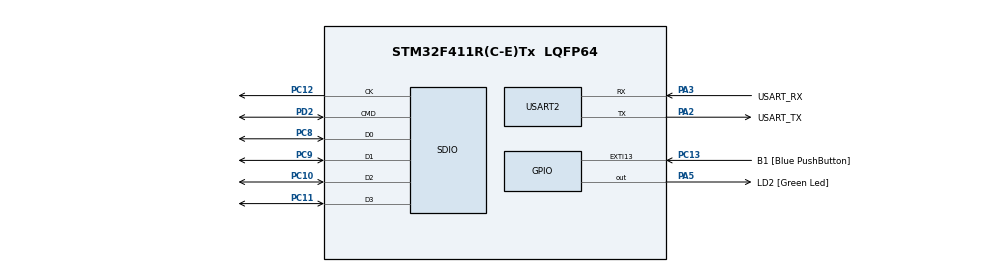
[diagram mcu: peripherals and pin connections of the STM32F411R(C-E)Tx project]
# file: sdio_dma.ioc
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Dma.Request0=SDIO_RX
Dma.Request1=SDIO_TX
Dma.SDIO_RX.0.Direction=DMA_PERIPH_TO_MEMORY
Dma.SDIO_RX.0.FIFOMode=DMA_FIFOMODE_ENABLE
Dma.SDIO_RX.0.FIFOThreshold=DMA_FIFO_THRESHOLD_FULL
Dma.SDIO_RX.0.Instance=DMA2_Stream3
Dma.SDIO_RX.0.MemBurst=DMA_MBURST_INC4
Dma.SDIO_RX.0.MemDataAlignment=DMA_MDATAALIGN_WORD
Dma.SDIO_RX.0.MemInc=DMA_MINC_ENABLE
Dma.SDIO_RX.0.Mode=DMA_PFCTRL
Dma.SDIO_RX.0.PeriphBurst=DMA_PBURST_INC4
Dma.SDIO_RX.0.PeriphDataAlignment=DMA_PDATAALIGN_WORD
Dma.SDIO_RX.0.PeriphInc=DMA_PINC_DISABLE
Dma.SDIO_RX.0.Priority=DMA_PRIORITY_HIGH
Dma.SDIO_TX.1.Direction=DMA_MEMORY_TO_PERIPH
Dma.SDIO_TX.1.FIFOMode=DMA_FIFOMODE_ENABLE
Dma.SDIO_TX.1.FIFOThreshold=DMA_FIFO_THRESHOLD_FULL
Dma.SDIO_TX.1.Instance=DMA2_Stream6
Dma.SDIO_TX.1.MemBurst=DMA_MBURST_INC4
Dma.SDIO_TX.1.MemDataAlignment=DMA_MDATAALIGN_WORD
Dma.SDIO_TX.1.MemInc=DMA_MINC_ENABLE
Dma.SDIO_TX.1.Mode=DMA_PFCTRL
Dma.SDIO_TX.1.PeriphBurst=DMA_PBURST_INC4
Dma.SDIO_TX.1.PeriphDataAlignment=DMA_PDATAALIGN_WORD
Dma.SDIO_TX.1.PeriphInc=DMA_PINC_DISABLE
Dma.SDIO_TX.1.Priority=DMA_PRIORITY_HIGH
FATFS.USE_DMA_CODE_SD=1
FATFS._MAX_SS=4096
Mcu.Family=STM32F4
Mcu.Name=STM32F411R(C-E)Tx
Mcu.Package=LQFP64
NVIC.DMA2_Stream3_IRQn=true\:0\:0\:false\:false\:true\:false\:true\:true
NVIC.DMA2_Stream6_IRQn=true\:0\:0\:false\:false\:true\:false\:true\:true
NVIC.PriorityGroup=NVIC_PRIORITYGROUP_0
NVIC.SDIO_IRQn=true\:0\:0\:false\:false\:true\:true\:true\:true
PA13.GPIO_Label=TMS
PA13.Mode=Serial_Wire
PA13.Signal=SYS_JTMS-SWDIO
PA14.GPIO_Label=TCK
PA14.Mode=Serial_Wire
PA14.Signal=SYS_JTCK-SWCLK
PA2.GPIO_Label=USART_TX
PA2.Mode=Asynchronous
PA2.Signal=USART2_TX
PA3.GPIO_Label=USART_RX
PA3.Mode=Asynchronous
PA3.Signal=USART2_RX
PA5.GPIO_Label=LD2 [Green Led]
PA5.Signal=GPIO_Output
PB3.GPIO_Label=SWO
PB3.Signal=SYS_JTDO-SWO
PC10.GPIO_PuPd=GPIO_PULLUP
PC10.Mode=SD_4_bits_Wide_bus
PC10.Signal=SDIO_D2
PC11.GPIO_PuPd=GPIO_PULLUP
PC11.Mode=SD_4_bits_Wide_bus
PC11.Signal=SDIO_D3
PC12.Mode=SD_4_bits_Wide_bus
PC12.Signal=SDIO_CK
PC13-ANTI_TAMP.GPIO_Label=B1 [Blue PushButton]
PC13-ANTI_TAMP.GPIO_ModeDefaultEXTI=GPIO_MODE_IT_FALLING
PC13-ANTI_TAMP.Signal=GPXTI13
PC14-OSC32_IN.Mode=LSE-External-Oscillator
PC14-OSC32_IN.Signal=RCC_OSC32_IN
PC15-OSC32_OUT.Mode=LSE-External-Oscillator
PC15-OSC32_OUT.Signal=RCC_OSC32_OUT
PC8.GPIO_PuPd=GPIO_PULLUP
PC8.Mode=SD_4_bits_Wide_bus
PC8.Signal=SDIO_D0
PC9.GPIO_PuPd=GPIO_PULLUP
PC9.Mode=SD_4_bits_Wide_bus
PC9.Signal=SDIO_D1
PD2.GPIO_PuPd=GPIO_PULLUP
PD2.Mode=SD_4_bits_Wide_bus
PD2.Signal=SDIO_CMD
PH0\ -\ OSC_IN.Mode=HSE-External-Clock-Source
PH0\ -\ OSC_IN.Signal=RCC_OSC_IN
PH1\ -\ OSC_OUT.Mode=HSE-External-Clock-Source
PH1\ -\ OSC_OUT.Signal=RCC_OSC_OUT
ProjectManager.HeapSize=0x2000
ProjectManager.StackSize=0x4000
ProjectManager.TargetToolchain=STM32CubeIDE
RCC.48MHZClocksFreq_Value=48000000
RCC.AHBFreq_Value=36000000
RCC.APB1Freq_Value=36000000
RCC.APB1TimFreq_Value=36000000
RCC.APB2Freq_Value=36000000
RCC.APB2TimFreq_Value=36000000
RCC.CortexFreq_Value=36000000
RCC.FLatency-AdvancedSettings=FLASH_LATENCY_1
RCC.HCLKFreq_Value=36000000
RCC.HSE_VALUE=8000000
RCC.HSI_VALUE=16000000
RCC.PLLM=4
RCC.PLLN=72
RCC.PLLP=RCC_PLLP_DIV4
RCC.PLLQ=3
RCC.PLLSourceVirtual=RCC_PLLSOURCE_HSE
RCC.SYSCLKFreq_VALUE=36000000
RCC.SYSCLKSource=RCC_SYSCLKSOURCE_PLLCLK
RCC.VCOOutputFreq_Value=144000000
SDIO.HardwareFlowControl=SDIO_HARDWARE_FLOW_CONTROL_ENABLE
USART2.VirtualMode=VM_ASYNC
VP_FATFS_VS_SDIO.Mode=SDIO
board=NUCLEO-F411RE

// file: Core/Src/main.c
/* USER CODE BEGIN Header */
/**
  ******************************************************************************
  * @file           : main.c
  * @brief          : SDIO + FatFs (SAFE FLOW)
  *                  1bit init -> mount -> (optional) switch to 4bit
  *
  *                  added Sequential RAW data logging prototype
  *                  1 extent = 4kB
  *                  1 data packet = 64B (not fixed)
  *
  *                  Superblock Logging -> Navigate to Write Data sequentially, append-only
  *
  *                  BSP_driver_sd files are utilized, not modified
  *                  No more usage of FATFS  related Libraries
  *
  *
  ******************************************************************************
  */
/* USER CODE END Header */

#include "main.h"
#include "gpio.h"
#include "usart.h"
#include "sdio.h"
#include "fatfs.h"

/* USER CODE BEGIN Includes */
#include <stdio.h>
#include <string.h>
#include "bsp_driver_sd.h"
#include "ff.h"
/* USER CODE END Includes */

/* USER CODE BEGIN PV */
extern SD_HandleTypeDef hsd;/* Includes ------------------------------------------------------------------*/
#include "main.h"
#include "gpio.h"
#include "usart.h"
#include "sdio.h"
#include "fatfs.h"
#include "dma.h"

/* USER CODE BEGIN Includes */
#include <stdio.h>
#include <string.h>
#include "ff.h"
/* USER CODE END Includes */

/* USER CODE BEGIN PV */
extern SD_HandleTypeDef hsd;

extern FATFS SDFatFS;
extern FIL   SDFile;
extern char  SDPath[4];   // "0:/"

static uint32_t g_seq = 0;
/* USER CODE END PV */

void SystemClock_Config(void);

/* USER CODE BEGIN 0 */
static void die(const char *tag, int code)
{
  printf("[DIE] %s code=%d hsd_err=0x%08lX\r\n",
         tag, code, (unsigned long)HAL_SD_GetError(&hsd));
  Error_Handler();
}
/* USER CODE END 0 */

int main(void)
{
  HAL_Init();
  SystemClock_Config();

  MX_GPIO_Init();
  MX_USART2_UART_Init();
  MX_DMA_Init();
  MX_SDIO_SD_Init();    // SDIO 핀/인스턴스 세팅(핵심 init은 아래 HAL_SD_Init)
  MX_FATFS_Init();      // FatFs driver link

  printf("\r\n[BOOT] SDIO + FatFs minimal (1bit init -> mount -> optional 4bit)\r\n");

  /* ========================= */
  /* [BP1] SD CARD INIT (ONCE) */
  /* ========================= */
  // ✅ BP1: 여기 걸고 hsd.Init.BusWide / ClockDiv 확인
  if (HAL_SD_Init(&hsd) != HAL_OK)
    die("HAL_SD_Init", 1);

  // ( MX_SDIO_SD_Init에서 1bit로 시작하게 되어있음)
  // HAL_SD_ConfigWideBusOperation(&hsd, SDIO_BUS_WIDE_1B);  sd diskio에서 이미 됨

  /* ===================== */
  /* [BP2] FATFS MOUNT      */
  /* ===================== */
  // BP2: 여기서 fr이 FR_DISK_ERR면 "diskio read 실패" 쪽(거의 sd_diskio.c/IRQ/클럭)
  FRESULT fr = f_mount(&SDFatFS, (TCHAR const*)SDPath, 1);
  if (fr != FR_OK)
  {
    printf("[FATFS] mount fail fr=%d hsd_err=0x%08lX\r\n",
           (int)fr, (unsigned long)HAL_SD_GetError(&hsd));
    die("f_mount", (int)fr);
  }
  printf("[FATFS] mount OK\r\n");

  /* ============================= */
  /* [BP3] OPTIONAL: SWITCH 4-BIT  */
  /* ============================= */
  // BP3: 4bit 실패하면 배선/D1~D3 풀업/신호무결성 쪽 가능성 큼 → 그냥 1bit로 계속 가
  hsd.Init.ClockDiv = 2;   // 48MHz / 6 = 8MHz
hsd.Init.BusWide = SDIO_BUS_WIDE_4B;

//  if (HAL_SD_ConfigWideBusOperation(&hsd, SDIO_BUS_WIDE_4B) == HAL_OK)
//    printf("[SDIO] 4bit OK\r\n");
//  else
//    printf("[SDIO] 4bit FAIL -> keep 1bit (hsd_err=0x%08lX)\r\n",
//           (unsigned long)HAL_SD_GetError(&hsd));

  /* ===================== */
  /* [BP4] FILE OPEN/APPEND */
  /* ===================== */
  // BP4: 여기서부터는 파일시스템 레벨
  fr = f_open(&SDFile, "log.txt", FA_OPEN_ALWAYS | FA_WRITE);
  if (fr != FR_OK) die("f_open", (int)fr);

  fr = f_lseek(&SDFile, f_size(&SDFile));
  if (fr != FR_OK) die("f_lseek", (int)fr);

  if (f_size(&SDFile) == 0U)
  {
    UINT bw;
    const char *hdr = "t_ms,seq,hsd_err\r\n";
    fr = f_write(&SDFile, hdr, (UINT)strlen(hdr), &bw);
    if (fr != FR_OK || bw != (UINT)strlen(hdr)) die("header_write", (int)fr);
    (void)f_sync(&SDFile);
  }

  /* ============ LOOP ============ */
  while (1)
  {
    char line[96];
    UINT bw;
   volatile UINT dummy = 0;

    uint32_t t   = HAL_GetTick();
    uint32_t err = HAL_SD_GetError(&hsd);

    int n = snprintf(line, sizeof(line),
                     "%lu,%lu,0x%08lX\r\n",
                     (unsigned long)t,
                     (unsigned long)g_seq++,
                     (unsigned long)err);

    fr = f_write(&SDFile, line, (UINT)n, &bw);
    if (fr != FR_OK || bw != (UINT)n) die("f_write", (int)fr);

    if ((g_seq % 5000U) == 0U)
    {
      fr = f_sync(&SDFile);
      if (fr != FR_OK) die("f_sync", (int)fr);
    }

    dummy++;
  }
}

void SystemClock_Config(void)
{
  RCC_OscInitTypeDef RCC_OscInitStruct = {0};
  RCC_ClkInitTypeDef RCC_ClkInitStruct = {0};

  __HAL_RCC_PWR_CLK_ENABLE();
  __HAL_PWR_VOLTAGESCALING_CONFIG(PWR_REGULATOR_VOLTAGE_SCALE1);

  RCC_OscInitStruct.OscillatorType = RCC_OSCILLATORTYPE_HSE;
  RCC_OscInitStruct.HSEState       = RCC_HSE_BYPASS;
  RCC_OscInitStruct.PLL.PLLState   = RCC_PLL_ON;
  RCC_OscInitStruct.PLL.PLLSource  = RCC_PLLSOURCE_HSE;

  // HSE=8MHz 가정
  // VCO = 8/4*72 = 144MHz
  // SYSCLK = 144/2 = 72MHz
  // PLL48CLK = 144/3 = 48MHz  ✅ (SDIO/USB 쪽)
  RCC_OscInitStruct.PLL.PLLM = 4;
  RCC_OscInitStruct.PLL.PLLN = 72;
  RCC_OscInitStruct.PLL.PLLP = RCC_PLLP_DIV2;
  RCC_OscInitStruct.PLL.PLLQ = 3;

  if (HAL_RCC_OscConfig(&RCC_OscInitStruct) != HAL_OK)
    Error_Handler();

  RCC_ClkInitStruct.ClockType =
      RCC_CLOCKTYPE_HCLK | RCC_CLOCKTYPE_SYSCLK |
      RCC_CLOCKTYPE_PCLK1 | RCC_CLOCKTYPE_PCLK2;
  RCC_ClkInitStruct.SYSCLKSource   = RCC_SYSCLKSOURCE_PLLCLK;
  RCC_ClkInitStruct.AHBCLKDivider  = RCC_SYSCLK_DIV1;
  RCC_ClkInitStruct.APB1CLKDivider = RCC_HCLK_DIV2; // ✅ APB1 36MHz
  RCC_ClkInitStruct.APB2CLKDivider = RCC_HCLK_DIV1; // ✅ APB2 72MHz

  if (HAL_RCC_ClockConfig(&RCC_ClkInitStruct, FLASH_LATENCY_2) != HAL_OK)
    Error_Handler();
}

void Error_Handler(void)
{
  __disable_irq();
  while (1) { }
}
